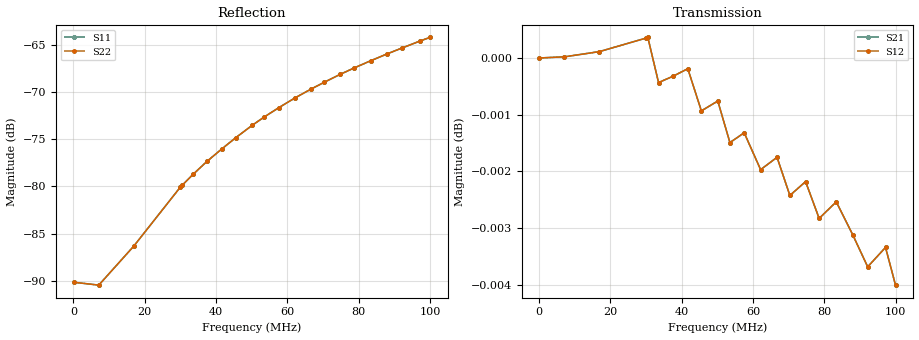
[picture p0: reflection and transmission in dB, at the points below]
! ListType=Lin
!!SAA-2 female thru 0.1 to 100MHz 500 points
# MHZ S RI R 50
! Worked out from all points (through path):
!   500 points, 100 kHz to 100 MHz, reference 50 ohm
!   highest |S21| = 0.00 dB at 100 kHz (marker M1); lowest = 0.0 dB at 100 MHz (marker M2)
!   lowest |S11| = -90.5 dB at 7.107 MHz (marker M3), VSWR 1.00, Z = 50 + j0.0029 ohm
!   |S11| at or under -10 dB: start of sweep to end of sweep
!   |S22| runs from -90.5 to -64.2 dB; largest |S21 - S12| = 0
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0.1  -2.04e-05 2.34e-05  1 -2.47e-05  1 -2.47e-05  -2.04e-05 2.34e-05
7.107014  -7.6e-06 2.9e-05  1 -0.00215  1 -0.00215  -7.6e-06 2.9e-05
16.91683  3.42e-05 3.4e-05  1 -0.00508  1 -0.00508  3.42e-05 3.4e-05
29.92986  9.66e-05 2.05e-05  1 -0.00897  1 -0.00897  9.66e-05 2.05e-05
30.53046  9.96e-05 1.93e-05  1 -0.00915  1 -0.00915  9.96e-05 1.93e-05
33.53347  0.000115 1.25e-05  0.9999 -0.01  0.9999 -0.01  0.000115 1.25e-05
37.53747  0.000136 1.4e-06  0.9999 -0.0112  0.9999 -0.0112  0.000136 1.4e-06
41.74168  0.000158 -1.26e-05  0.9999 -0.0125  0.9999 -0.0125  0.000158 -1.26e-05
45.54549  0.000179 -2.74e-05  0.9998 -0.0136  0.9998 -0.0136  0.000179 -2.74e-05
50.1501  0.000205 -4.81e-05  0.9998 -0.015  0.9998 -0.015  0.000205 -4.81e-05
53.55351  0.000224 -6.5e-05  0.9997 -0.016  0.9997 -0.016  0.000224 -6.5e-05
57.55752  0.000246 -8.62e-05  0.9997 -0.0172  0.9997 -0.0172  0.000246 -8.62e-05
62.16212  0.000272 -0.000112  0.9996 -0.0186  0.9996 -0.0186  0.000272 -0.000112
66.76673  0.000297 -0.00014  0.9996 -0.0199  0.9996 -0.0199  0.000297 -0.00014
70.37034  0.000316 -0.000164  0.9995 -0.021  0.9995 -0.021  0.000316 -0.000164
74.77475  0.00034 -0.000194  0.9995 -0.0223  0.9995 -0.0223  0.00034 -0.000194
78.57856  0.00036 -0.000221  0.9994 -0.0234  0.9994 -0.0234  0.00036 -0.000221
83.38337  0.000384 -0.000258  0.9994 -0.0248  0.9994 -0.0248  0.000384 -0.000258
87.98798  0.000408 -0.000294  0.9993 -0.0261  0.9993 -0.0261  0.000408 -0.000294
92.19218  0.000429 -0.000329  0.9992 -0.0274  0.9992 -0.0274  0.000429 -0.000329
97.19719  0.000454 -0.000374  0.9992 -0.0288  0.9992 -0.0288  0.000454 -0.000374
100  0.000468 -0.000399  0.9991 -0.0296  0.9991 -0.0296  0.000468 -0.000399
